VERSION 5.8 ;
BUSBITCHARS "[]" ;
DIVIDERCHAR "/" ;
UNITS
    DATABASE MICRONS 1000 ;
END UNITS

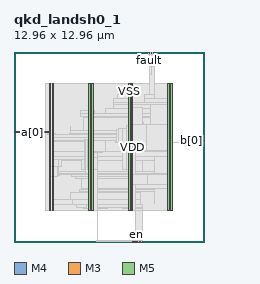
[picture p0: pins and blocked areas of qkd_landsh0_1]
MACRO qkd_landsh0_1
  FOREIGN qkd_landsh0_1 0 0 ;
  CLASS BLOCK ;
  SIZE 12.96 BY 12.96 ;
  PIN a[0]
    DIRECTION INPUT ;
    USE SIGNAL ;
    PORT
      LAYER M4 ;
        RECT  0 7.488 0.084 7.512 ;
    END
    PORT
      LAYER M4 ;
        RECT  0.06 7.488 2.408 7.512 ;
    END
  END a[0]
  PIN b[0]
    DIRECTION OUTPUT ;
    USE SIGNAL ;
    PORT
      LAYER M4 ;
        RECT  12.876 6.912 12.96 6.936 ;
    END
    PORT
      LAYER M4 ;
        RECT  11.977 6.912 12.924 6.936 ;
    END
  END b[0]
  PIN ck
    DIRECTION INPUT ;
    USE SIGNAL ;
    PORT
      LAYER M3 ;
        RECT  8.1 0 8.118 0.037 ;
    END
  END ck
  PIN ck_s
    DIRECTION INPUT ;
    USE SIGNAL ;
    PORT
      LAYER M3 ;
        RECT  8.208 0 8.226 0.037 ;
    END
  END ck_s
  PIN en
    DIRECTION INPUT ;
    USE SIGNAL ;
    PORT
      LAYER M3 ;
        RECT  8.316 0 8.334 0.037 ;
    END
  END en
  PIN fault
    DIRECTION OUTPUT ;
    USE SIGNAL ;
    PORT
      LAYER M5 ;
        RECT  9.216 12.876 9.24 12.96 ;
    END
  END fault
  PIN k0
    DIRECTION INPUT ;
    USE SIGNAL ;
    PORT
      LAYER M3 ;
        RECT  8.424 0 8.442 0.037 ;
    END
  END k0
  PIN k1
    DIRECTION INPUT ;
    USE SIGNAL ;
    PORT
      LAYER M3 ;
        RECT  8.532 0 8.55 0.037 ;
    END
  END k1
  PIN k2
    DIRECTION INPUT ;
    USE SIGNAL ;
    PORT
      LAYER M3 ;
        RECT  8.64 0 8.658 0.037 ;
    END
  END k2
  PIN rs
    DIRECTION INPUT ;
    USE SIGNAL ;
    PORT
      LAYER M3 ;
        RECT  8.748 0 8.766 0.037 ;
    END
  END rs
  PIN tie_hi
    DIRECTION OUTPUT ;
    USE SIGNAL ;
    PORT
      LAYER M5 ;
        RECT  9.36 12.876 9.384 12.96 ;
    END
  END tie_hi
  PIN tie_lo
    DIRECTION OUTPUT ;
    USE SIGNAL ;
    PORT
      LAYER M5 ;
        RECT  9.504 12.876 9.528 12.96 ;
    END
  END tie_lo
  PIN VDD
    DIRECTION INOUT ;
    USE POWER ;
    PORT
      LAYER M5 ;
        RECT  10.692 2.151 10.812 10.809 ;
        RECT  7.992 2.151 8.112 10.809 ;
        RECT  5.292 2.151 5.412 10.809 ;
        RECT  2.592 2.151 2.712 10.809 ;
    END
  END VDD
  PIN VSS
    DIRECTION INOUT ;
    USE GROUND ;
    PORT
      LAYER M5 ;
        RECT  10.5 2.137 10.62 10.823 ;
        RECT  7.8 2.137 7.92 10.823 ;
        RECT  5.1 2.137 5.22 10.823 ;
        RECT  2.4 2.137 2.52 10.823 ;
    END
  END VSS
  # OT_OBS_CLOSED layer=M5 d_um=1.536 added=4
  OBS
    LAYER RVTN ;
     RECT  2.16 2.16 10.8 2.295 ;
     RECT  2.16 2.565 10.8 2.835 ;
     RECT  2.16 3.105 10.8 3.375 ;
     RECT  2.16 3.645 10.8 3.915 ;
     RECT  2.16 4.185 10.8 4.455 ;
     RECT  2.16 4.725 10.8 4.995 ;
     RECT  2.16 5.265 10.8 5.535 ;
     RECT  2.16 5.805 10.8 6.075 ;
     RECT  2.16 6.345 10.8 6.615 ;
     RECT  2.16 6.885 10.8 7.155 ;
     RECT  2.16 7.425 10.8 7.695 ;
     RECT  2.16 7.965 10.8 8.235 ;
     RECT  2.16 8.505 10.8 8.775 ;
     RECT  2.16 9.045 10.8 9.315 ;
     RECT  2.16 9.585 10.8 9.855 ;
     RECT  2.16 10.125 10.8 10.395 ;
     RECT  2.16 10.665 10.8 10.8 ;
    LAYER RVTP ;
     RECT  2.16 2.295 10.8 2.565 ;
     RECT  2.16 2.835 10.8 3.105 ;
     RECT  2.16 3.375 10.8 3.645 ;
     RECT  2.16 3.915 10.8 4.185 ;
     RECT  2.16 4.455 10.8 4.725 ;
     RECT  2.16 4.995 10.8 5.265 ;
     RECT  2.16 5.535 10.8 5.805 ;
     RECT  2.16 6.075 10.8 6.345 ;
     RECT  2.16 6.615 10.8 6.885 ;
     RECT  2.16 7.155 10.8 7.425 ;
     RECT  2.16 7.695 10.8 7.965 ;
     RECT  2.16 8.235 10.8 8.505 ;
     RECT  2.16 8.775 10.8 9.045 ;
     RECT  2.16 9.315 10.8 9.585 ;
     RECT  2.16 9.855 10.8 10.125 ;
     RECT  2.16 10.395 10.8 10.665 ;
    LAYER M1 ;
     RECT  2.16 2.151 10.8 10.809 ;
    LAYER M2 ;
     RECT  7.915 0.036 8.231 0.054 ;
     RECT  2.16 2.151 10.8 10.809 ;
     RECT  10.8 2.421 10.812 10.539 ;
     RECT  10.812 6.786 12.011 6.804 ;
    LAYER M3 ;
     RECT  8.118 0.012 8.208 0.031 ;
     RECT  8.226 0.012 8.316 0.031 ;
     RECT  8.334 0.012 8.424 0.031 ;
     RECT  8.442 0.012 8.532 0.031 ;
     RECT  8.55 0.012 8.64 0.031 ;
     RECT  8.658 0.012 8.748 0.031 ;
     RECT  7.92 0.031 8.1 0.037 ;
     RECT  8.118 0.031 8.208 0.037 ;
     RECT  8.226 0.031 8.316 0.037 ;
     RECT  8.334 0.031 8.424 0.037 ;
     RECT  8.442 0.031 8.532 0.037 ;
     RECT  8.55 0.031 8.64 0.037 ;
     RECT  8.658 0.031 8.748 0.037 ;
     RECT  7.92 0.037 8.766 0.077 ;
     RECT  8.1 0.077 8.766 0.125 ;
     RECT  8.316 0.125 8.766 2.143 ;
     RECT  5.115 2.143 5.205 2.191 ;
     RECT  5.076 2.191 5.205 2.251 ;
     RECT  4.932 2.251 5.205 2.299 ;
     RECT  7.815 2.143 8.766 2.299 ;
     RECT  4.752 2.299 5.526 2.335 ;
     RECT  6.336 2.251 6.354 2.335 ;
     RECT  7.416 2.299 8.766 2.335 ;
     RECT  4.284 2.335 6.354 2.371 ;
     RECT  7.2 2.335 8.766 2.371 ;
     RECT  2.415 2.143 2.505 2.413 ;
     RECT  10.515 2.143 10.605 2.413 ;
     RECT  4.284 2.371 8.766 2.525 ;
     RECT  4.284 2.525 8.658 2.875 ;
     RECT  3.852 2.875 8.658 3.371 ;
     RECT  4.464 3.371 8.658 3.451 ;
     RECT  9.576 2.641 9.594 3.451 ;
     RECT  4.464 3.451 9.594 3.569 ;
     RECT  10.515 2.413 10.797 3.613 ;
     RECT  4.572 3.569 9.594 3.649 ;
     RECT  10.44 3.613 10.797 3.649 ;
     RECT  4.572 3.649 10.797 4.351 ;
     RECT  2.415 2.413 2.697 4.495 ;
     RECT  4.176 4.351 10.797 4.495 ;
     RECT  2.415 4.495 2.97 4.531 ;
     RECT  2.415 4.531 3.114 4.621 ;
     RECT  3.888 4.495 10.797 4.621 ;
     RECT  2.415 4.621 10.797 4.649 ;
     RECT  2.415 4.649 9.594 4.829 ;
     RECT  2.415 4.829 8.766 5.575 ;
     RECT  9.576 4.829 9.594 5.575 ;
     RECT  2.415 5.575 9.594 5.845 ;
     RECT  10.515 4.649 10.797 5.845 ;
     RECT  2.415 5.845 10.797 6.143 ;
     RECT  2.415 6.143 5.397 6.925 ;
     RECT  6.264 6.143 9.666 6.925 ;
     RECT  11.988 6.781 12.006 6.941 ;
     RECT  2.415 6.925 9.666 7.159 ;
     RECT  10.515 6.143 10.797 7.159 ;
     RECT  2.415 7.159 10.797 7.349 ;
     RECT  2.415 7.349 2.862 7.357 ;
     RECT  2.304 7.357 2.862 7.385 ;
     RECT  3.816 7.349 10.797 7.385 ;
     RECT  3.816 7.385 9.342 7.421 ;
     RECT  2.304 7.385 2.697 7.517 ;
     RECT  3.852 7.421 9.342 7.619 ;
     RECT  3.852 7.619 3.87 7.889 ;
     RECT  4.752 7.619 9.342 8.509 ;
     RECT  4.716 8.509 9.342 8.539 ;
     RECT  4.536 8.539 9.342 8.771 ;
     RECT  4.536 8.771 5.49 8.969 ;
     RECT  6.264 8.771 9.342 9.113 ;
     RECT  6.804 9.113 9.342 9.391 ;
     RECT  10.515 7.385 10.797 9.391 ;
     RECT  6.804 9.391 10.797 9.509 ;
     RECT  8.928 9.509 10.797 9.779 ;
     RECT  6.804 9.509 8.097 9.815 ;
     RECT  8.928 9.779 9.702 9.815 ;
     RECT  7.056 9.815 8.097 10.049 ;
     RECT  7.056 10.049 7.074 10.085 ;
     RECT  8.928 9.815 9.558 10.085 ;
     RECT  2.415 7.517 2.697 10.547 ;
     RECT  5.115 8.969 5.397 10.547 ;
     RECT  7.815 10.049 8.097 10.547 ;
     RECT  10.515 9.779 10.797 10.547 ;
     RECT  2.415 10.547 2.505 10.817 ;
     RECT  5.115 10.547 5.205 10.817 ;
     RECT  7.815 10.547 7.905 10.817 ;
     RECT  10.515 10.547 10.605 10.817 ;
     RECT  9.252 10.085 9.558 11.981 ;
     RECT  9.252 11.981 9.27 12.845 ;
    LAYER M4 ;
     RECT  2.408 2.148 2.512 10.812 ;
     RECT  2.512 2.418 2.704 10.542 ;
     RECT  2.704 4.512 3.011 5.64 ;
     RECT  3.011 5.136 3.233 5.64 ;
     RECT  3.841 2.88 3.973 2.904 ;
     RECT  3.233 5.616 4.633 5.64 ;
     RECT  4.633 4.944 4.813 5.64 ;
     RECT  2.704 6.864 4.813 6.888 ;
     RECT  4.813 4.944 4.849 6.984 ;
     RECT  3.973 2.592 4.921 2.904 ;
     RECT  4.921 2.256 5.108 2.904 ;
     RECT  4.849 4.656 5.108 6.984 ;
     RECT  4.525 8.544 5.108 8.568 ;
     RECT  5.108 2.148 5.212 10.812 ;
     RECT  5.212 2.256 5.404 10.542 ;
     RECT  5.404 4.656 5.465 4.68 ;
     RECT  5.404 5.712 5.725 6.12 ;
     RECT  5.725 6.096 6.041 6.12 ;
     RECT  5.404 2.256 6.365 2.28 ;
     RECT  5.404 3.6 6.365 3.624 ;
     RECT  6.937 6.816 7.009 6.84 ;
     RECT  7.009 6.816 7.153 7.704 ;
     RECT  7.045 5.808 7.369 5.832 ;
     RECT  7.153 6.816 7.369 7.752 ;
     RECT  7.369 5.808 7.405 7.752 ;
     RECT  7.405 4.944 7.657 7.752 ;
     RECT  7.657 4.944 7.808 7.944 ;
     RECT  7.808 2.148 7.912 10.812 ;
     RECT  5.653 0.048 7.949 0.072 ;
     RECT  7.912 2.418 8.104 10.542 ;
     RECT  8.104 5.808 8.273 9.144 ;
     RECT  8.089 0.096 8.291 0.12 ;
     RECT  8.273 6.24 8.771 9.144 ;
     RECT  8.771 6.24 8.813 8.184 ;
     RECT  8.813 6.24 9.073 7.992 ;
     RECT  9.073 7.056 9.1 7.08 ;
     RECT  8.104 3.936 9.107 4.584 ;
     RECT  9.107 3.936 9.173 3.96 ;
     RECT  9.197 12.816 9.281 12.84 ;
     RECT  9.308 11.424 9.395 11.448 ;
     RECT  9.485 11.952 9.569 11.976 ;
     RECT  10.508 2.148 10.612 10.812 ;
     RECT  10.612 2.418 10.804 10.542 ;
    LAYER M5 ;
     RECT  5.664 0.037 5.688 2.137 ;
     RECT  8.256 0.085 8.28 2.137 ;
     RECT  2.4 2.137 2.52 2.151 ;
     RECT  10.5 2.137 10.62 2.151 ;
     RECT  3.984 2.581 4.008 2.915 ;
     RECT  7.8 2.137 8.28 3.925 ;
     RECT  2.4 2.151 2.712 4.501 ;
     RECT  7.8 3.925 9.096 4.595 ;
     RECT  5.1 2.137 5.688 4.933 ;
     RECT  2.4 4.501 3 5.171 ;
     RECT  4.992 4.933 5.688 5.747 ;
     RECT  7.8 4.595 8.28 6.229 ;
     RECT  4.992 5.747 5.412 6.995 ;
     RECT  7.8 6.229 9.048 8.003 ;
     RECT  7.8 8.003 8.76 9.155 ;
     RECT  2.4 5.171 2.712 10.809 ;
     RECT  5.1 6.995 5.412 10.809 ;
     RECT  7.8 9.155 8.112 10.809 ;
     RECT  10.5 2.151 10.812 10.809 ;
     RECT  2.4 10.809 2.52 10.823 ;
     RECT  5.1 10.809 5.22 10.823 ;
     RECT  7.8 10.809 7.92 10.823 ;
     RECT  10.5 10.809 10.62 10.823 ;
     RECT  9.36 11.413 9.384 11.941 ;
     RECT  9.36 11.941 9.528 12.805 ;
     RECT  9.216 12.805 9.528 12.876 ;
     RECT  9.24 12.876 9.36 12.944 ;
     RECT  9.384 12.876 9.504 12.944 ;
     RECT  2.712 2.581 3.984 2.915 ;
     RECT  4.008 2.581 5.1 2.915 ;
     RECT  9.096 3.925 10.5 4.595 ;
     RECT  9.048 6.229 10.5 8.003 ;
  END
END qkd_landsh0_1
END LIBRARY
